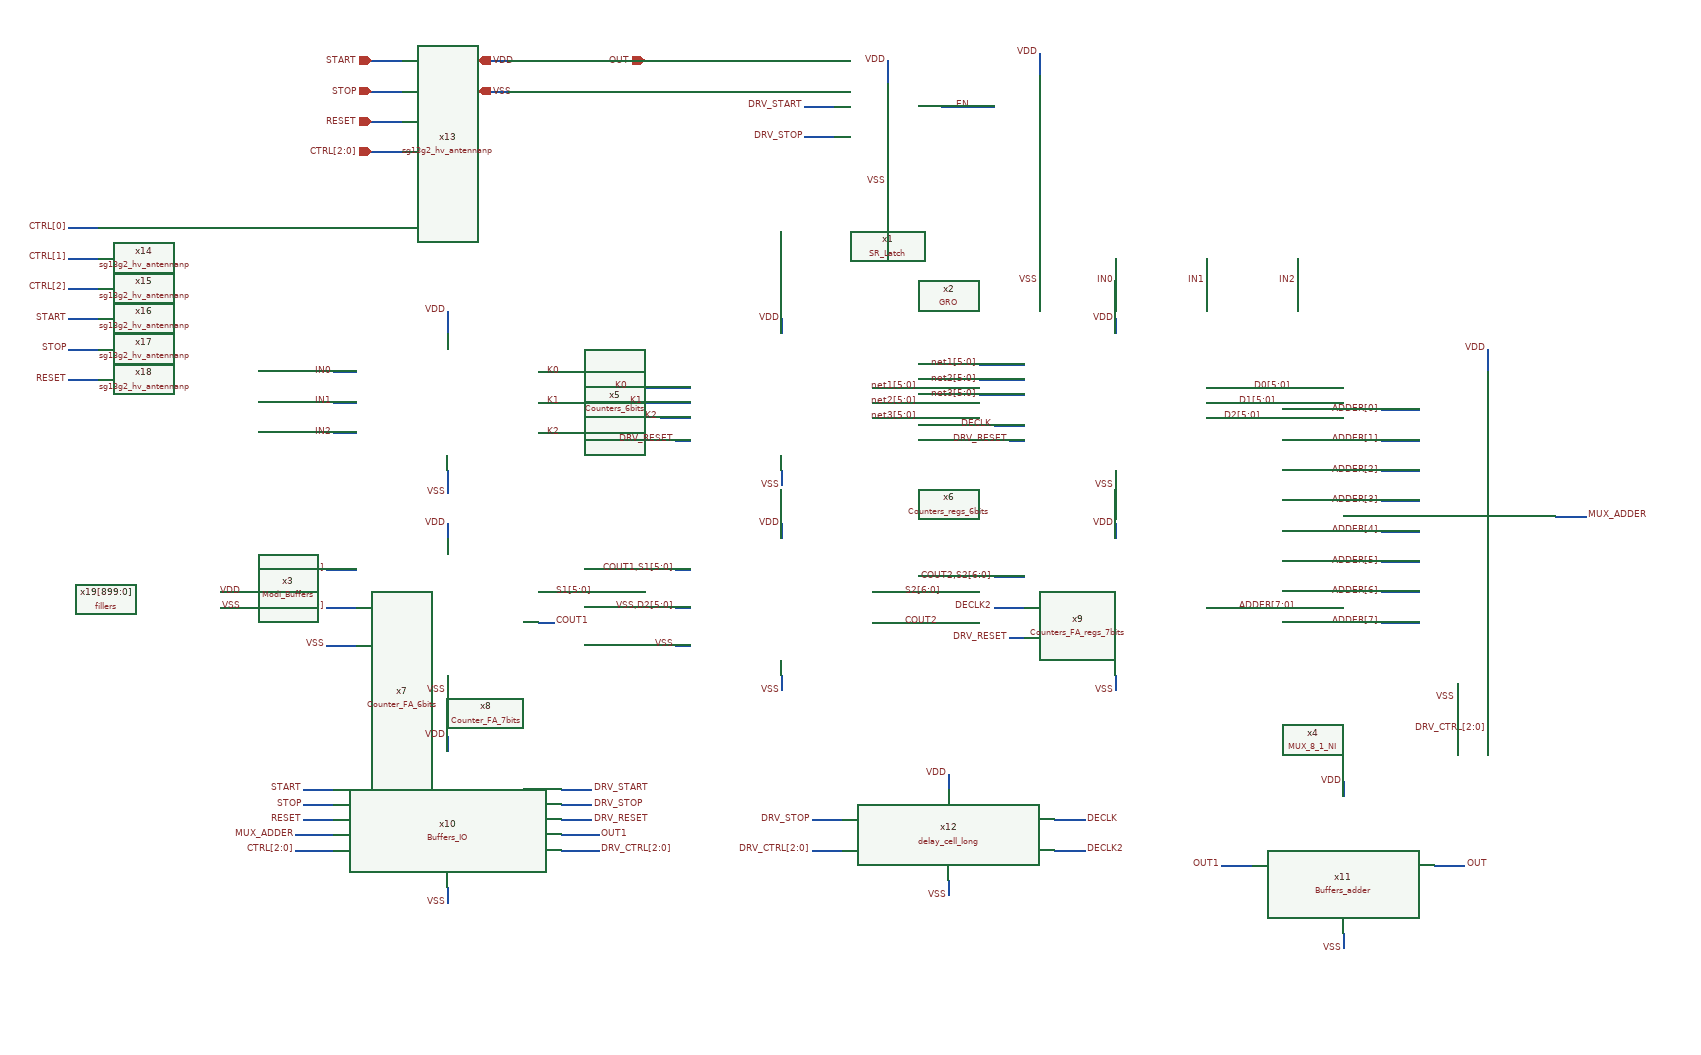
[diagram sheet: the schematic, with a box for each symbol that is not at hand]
v {xschem version=3.4.8RC file_version=1.3}
G {}
K {}
V {}
S {}
F {}
E {}
N 760 -850 760 -830 {lab=VDD}
N 1200 -850 1200 -830 {lab=VDD}
N 760 -650 760 -630 {lab=VSS}
N 1200 -650 1200 -630 {lab=VSS}
N 320 -580 320 -560 {lab=VDD}
N 760 -580 760 -560 {lab=VDD}
N 320 -380 320 -360 {lab=VSS}
N 760 -380 760 -360 {lab=VSS}
N 880 -490 920 -490 {lab=S2[6:0]}
N 880 -450 920 -450 {lab=COUT2}
N 1320 -760 1380 -760 {lab=D0[5:0]}
N 1320 -740 1360 -740 {lab=D1[5:0]}
N 1320 -720 1340 -720 {lab=D2[5:0]}
N 1040 -710 1080 -710 {lab=DECLK}
N 1060 -690 1080 -690 {lab=DRV_RESET}
N 880 -760 940 -760 {lab=net1[5:0]}
N 880 -720 940 -720 {lab=net3[5:0]}
N 620 -690 640 -690 {lab=DRV_RESET}
N 600 -720 640 -720 {lab=K2}
N 580 -740 640 -740 {lab=K1}
N 560 -760 640 -760 {lab=K0}
N 160 -520 200 -520 {lab=D0[5:0]}
N 160 -470 200 -470 {lab=D1[5:0]}
N 160 -420 200 -420 {lab=VSS}
N 440 -490 460 -490 {lab=S1[5:0]}
N 440 -450 460 -450 {lab=COUT1}
N 620 -420 640 -420 {lab=VSS}
N 620 -470 640 -470 {lab=VSS,D2[5:0]}
N 620 -520 640 -520 {lab=COUT1,S1[5:0]}
N 1200 -580 1200 -560 {lab=VDD}
N 1200 -380 1200 -360 {lab=VSS}
N 1320 -470 1360 -470 {lab=ADDER[7:0]}
N 1060 -430 1080 -430 {lab=DRV_RESET}
N 1040 -470 1080 -470 {lab=DECLK2}
N 220 -1190 260 -1190 {lab=START}
N 220 -1150 260 -1150 {lab=STOP}
N 220 -1110 260 -1110 {lab=RESET}
N 360 -1190 400 -1190 {lab=VDD}
N 360 -1150 400 -1150 {lab=VSS}
N 580 -1190 620 -1190 {lab=OUT}
N 1040 -510 1080 -510 {lab=COUT2,S2[6:0]}
N 790 -1130 830 -1130 {lab=DRV_START}
N 790 -1090 830 -1090 {lab=DRV_STOP}
N 900 -1190 900 -1160 {lab=VDD}
N 900 -1060 900 -1030 {lab=VSS}
N 1100 -1200 1100 -1170 {lab=VDD}
N 970 -1130 1040 -1130 {lab=EN}
N 1100 -930 1100 -900 {lab=VSS}
N 1200 -930 1200 -900 {lab=IN0}
N 1320 -930 1320 -900 {lab=IN1}
N 1440 -930 1440 -900 {lab=IN2}
N 320 -650 320 -620 {lab=VSS}
N 440 -780 470 -780 {lab=K0}
N 440 -740 470 -740 {lab=K1}
N 440 -700 470 -700 {lab=K2}
N 170 -780 200 -780 {lab=IN0}
N 170 -740 200 -740 {lab=IN1}
N 170 -700 200 -700 {lab=IN2}
N 320 -860 320 -830 {lab=VDD}
N 1690 -810 1690 -780 {lab=VDD}
N 1780 -590 1820 -590 {lab=MUX_ADDER}
N 1550 -730 1600 -730 {lab=ADDER[0]}
N 1550 -690 1600 -690 {lab=ADDER[1]}
N 1550 -650 1600 -650 {lab=ADDER[2]}
N 1550 -610 1600 -610 {lab=ADDER[3]}
N 1550 -570 1600 -570 {lab=ADDER[4]}
N 1550 -530 1600 -530 {lab=ADDER[5]}
N 1550 -490 1600 -490 {lab=ADDER[6]}
N 1550 -450 1600 -450 {lab=ADDER[7]}
N 1650 -370 1650 -350 {lab=VSS}
N 220 -1070 260 -1070 {lab=CTRL[2:0]}
N 320 -100 320 -80 {lab=VSS}
N 320 -300 320 -280 {lab=VDD}
N 130 -230 170 -230 {lab=START}
N 130 -210 170 -210 {lab=STOP}
N 130 -190 170 -190 {lab=RESET}
N 120 -170 170 -170 {lab=MUX_ADDER}
N 470 -230 510 -230 {lab=DRV_START}
N 470 -210 510 -210 {lab=DRV_STOP}
N 470 -190 510 -190 {lab=DRV_RESET}
N 470 -170 520 -170 {lab=OUT1}
N 1690 -370 1690 -310 {lab=DRV_CTRL[2:0]}
N 470 -150 520 -150 {lab=DRV_CTRL[2:0]}
N 120 -150 170 -150 {lab=CTRL[2:0]}
N 980 -110 980 -90 {lab=VSS}
N 980 -250 980 -230 {lab=VDD}
N 800 -190 840 -190 {lab=DRV_STOP}
N 1120 -190 1160 -190 {lab=DECLK}
N 1120 -150 1160 -150 {lab=DECLK2}
N 800 -150 840 -150 {lab=DRV_CTRL[2:0]}
N 1340 -130 1380 -130 {lab=OUT1}
N 1620 -130 1660 -130 {lab=OUT}
N 1500 -240 1500 -220 {lab=VDD}
N 1500 -40 1500 -20 {lab=VSS}
N -180 -970 -140 -970 {lab=CTRL[0]}
N -180 -930 -140 -930 {lab=CTRL[1]}
N -180 -890 -140 -890 {lab=CTRL[2]}
N -180 -850 -140 -850 {lab=START}
N -180 -810 -140 -810 {lab=STOP}
N -180 -770 -140 -770 {lab=RESET}
N 880 -740 940 -740 {lab=net2[5:0]}
N 1020 -790 1080 -790 {lab=net1[5:0]}
N 1020 -750 1080 -750 {lab=net3[5:0]}
N 1020 -770 1080 -770 {lab=net2[5:0]}
N 20 -470 50 -470 {lab=VSS}
N 20 -490 50 -490 {lab=VDD}
C {Counters_6bits.sym} 540 -590 0 0 {name=x5
}
C {Counters_regs_6bits.sym} 980 -560 0 0 {name=x6
}
C {Counter_FA_6bits.sym} 180 -380 0 0 {name=x7
}
C {Counter_FA_7bits.sym} 380 -300 0 0 {name=x8
}
C {lab_wire.sym} 760 -630 0 0 {name=p9 sig_type=std_logic lab=VSS
}
C {lab_wire.sym} 1200 -630 0 0 {name=p10 sig_type=std_logic lab=VSS
}
C {lab_wire.sym} 760 -360 0 0 {name=p11 sig_type=std_logic lab=VSS
}
C {lab_wire.sym} 320 -360 0 0 {name=p12 sig_type=std_logic lab=VSS
}
C {lab_wire.sym} 760 -850 0 0 {name=p13 sig_type=std_logic lab=VDD
}
C {lab_wire.sym} 1200 -850 0 0 {name=p14 sig_type=std_logic lab=VDD
}
C {lab_wire.sym} 760 -580 0 0 {name=p15 sig_type=std_logic lab=VDD
}
C {lab_wire.sym} 320 -580 0 0 {name=p16 sig_type=std_logic lab=VDD
}
C {lab_wire.sym} 580 -740 3 0 {name=p18 sig_type=std_logic lab=K1
}
C {lab_wire.sym} 560 -760 3 0 {name=p17 sig_type=std_logic lab=K0
}
C {lab_wire.sym} 600 -720 3 0 {name=p19 sig_type=std_logic lab=K2
}
C {lab_wire.sym} 1040 -710 3 0 {name=p21 sig_type=std_logic lab=DECLK
}
C {lab_wire.sym} 1060 -690 3 0 {name=p22 sig_type=std_logic lab=DRV_RESET
}
C {lab_wire.sym} 620 -520 0 0 {name=p23 sig_type=std_logic lab=COUT1,S1[5:0]
}
C {lab_wire.sym} 1380 -760 0 1 {name=p24 sig_type=std_logic lab=D0[5:0]
}
C {lab_wire.sym} 1360 -740 0 1 {name=p25 sig_type=std_logic lab=D1[5:0]
}
C {lab_wire.sym} 1340 -720 0 1 {name=p26 sig_type=std_logic lab=D2[5:0]
}
C {lab_wire.sym} 160 -520 0 0 {name=p27 sig_type=std_logic lab=D0[5:0]
}
C {lab_wire.sym} 160 -470 0 0 {name=p28 sig_type=std_logic lab=D1[5:0]
}
C {lab_wire.sym} 620 -470 0 0 {name=p29 sig_type=std_logic lab=VSS,D2[5:0]
}
C {lab_wire.sym} 160 -420 0 0 {name=p30 sig_type=std_logic lab=VSS
}
C {lab_wire.sym} 620 -420 0 0 {name=p31 sig_type=std_logic lab=VSS
}
C {lab_wire.sym} 460 -490 0 1 {name=p32 sig_type=std_logic lab=S1[5:0]
}
C {lab_wire.sym} 460 -450 0 1 {name=p33 sig_type=std_logic lab=COUT1
}
C {lab_wire.sym} 920 -450 0 1 {name=p35 sig_type=std_logic lab=COUT2
}
C {lab_wire.sym} 1200 -580 0 0 {name=p36 sig_type=std_logic lab=VDD
}
C {lab_wire.sym} 1200 -360 0 0 {name=p37 sig_type=std_logic lab=VSS
}
C {Counters_FA_regs_7bits.sym} 1040 -350 0 0 {name=x9
}
C {lab_wire.sym} 1360 -470 0 1 {name=p39 sig_type=std_logic lab=ADDER[7:0]
}
C {ipin.sym} 220 -1190 0 0 {name=p40 lab=START}
C {ipin.sym} 220 -1150 0 0 {name=p41 lab=STOP}
C {ipin.sym} 220 -1110 0 0 {name=p42 lab=RESET}
C {iopin.sym} 360 -1190 0 1 {name=p46 lab=VDD}
C {iopin.sym} 360 -1150 0 1 {name=p47 lab=VSS}
C {opin.sym} 580 -1190 0 1 {name=p48 lab=OUT}
C {lab_wire.sym} 920 -490 0 1 {name=p49 sig_type=std_logic lab=S2[6:0]
}
C {lab_wire.sym} 1040 -510 0 0 {name=p50 sig_type=std_logic lab=COUT2,S2[6:0]
}
C {lab_wire.sym} 900 -1030 0 0 {name=p2 sig_type=std_logic lab=VSS
}
C {lab_wire.sym} 1100 -1200 0 0 {name=p1 sig_type=std_logic lab=VDD
}
C {SR_Latch.sym} 810 -1020 0 0 {name=x1}
C {lab_wire.sym} 900 -1190 0 0 {name=p3 sig_type=std_logic lab=VDD
}
C {lab_wire.sym} 790 -1130 0 0 {name=p4 sig_type=std_logic lab=DRV_START
}
C {lab_wire.sym} 790 -1090 0 0 {name=p5 sig_type=std_logic lab=DRV_STOP
}
C {lab_wire.sym} 1010 -1130 0 0 {name=p6 sig_type=std_logic lab=EN
}
C {GRO.sym} 1040 -910 0 0 {name=x2
}
C {lab_wire.sym} 1100 -900 0 0 {name=p7 sig_type=std_logic lab=VSS
}
C {lab_wire.sym} 1200 -900 0 0 {name=p8 sig_type=std_logic lab=IN0
}
C {lab_wire.sym} 1320 -900 0 0 {name=p43 sig_type=std_logic lab=IN1
}
C {lab_wire.sym} 1440 -900 0 0 {name=p44 sig_type=std_logic lab=IN2
}
C {lab_wire.sym} 320 -620 0 0 {name=p51 sig_type=std_logic lab=VSS
}
C {Modi_Buffers.sym} 100 -560 0 0 {name=x3
}
C {lab_wire.sym} 470 -780 3 1 {name=p52 sig_type=std_logic lab=K0
}
C {lab_wire.sym} 470 -740 3 1 {name=p53 sig_type=std_logic lab=K1
}
C {lab_wire.sym} 470 -700 3 1 {name=p54 sig_type=std_logic lab=K2
}
C {lab_wire.sym} 170 -780 1 0 {name=p55 sig_type=std_logic lab=IN0
}
C {lab_wire.sym} 170 -740 1 0 {name=p56 sig_type=std_logic lab=IN1
}
C {lab_wire.sym} 170 -700 1 0 {name=p57 sig_type=std_logic lab=IN2
}
C {lab_wire.sym} 320 -860 0 0 {name=p58 sig_type=std_logic lab=VDD
}
C {lab_wire.sym} 1690 -810 0 0 {name=p59 sig_type=std_logic lab=VDD
}
C {lab_wire.sym} 1550 -730 0 0 {name=p60 sig_type=std_logic lab=ADDER[0]
}
C {lab_wire.sym} 1550 -690 0 0 {name=p61 sig_type=std_logic lab=ADDER[1]
}
C {lab_wire.sym} 1550 -650 0 0 {name=p62 sig_type=std_logic lab=ADDER[2]
}
C {lab_wire.sym} 1550 -610 0 0 {name=p63 sig_type=std_logic lab=ADDER[3]
}
C {lab_wire.sym} 1550 -570 0 0 {name=p64 sig_type=std_logic lab=ADDER[4]
}
C {lab_wire.sym} 1550 -530 0 0 {name=p65 sig_type=std_logic lab=ADDER[5]
}
C {lab_wire.sym} 1550 -490 0 0 {name=p66 sig_type=std_logic lab=ADDER[6]
}
C {lab_wire.sym} 1550 -450 0 0 {name=p67 sig_type=std_logic lab=ADDER[7]
}
C {lab_wire.sym} 1820 -590 0 1 {name=p68 sig_type=std_logic lab=MUX_ADDER
}
C {lab_wire.sym} 1650 -350 0 0 {name=p69 sig_type=std_logic lab=VSS
}
C {ipin.sym} 220 -1070 0 0 {name=p70 lab=CTRL[2:0]}
C {lab_wire.sym} 320 -80 0 0 {name=p71 sig_type=std_logic lab=VSS
}
C {lab_wire.sym} 320 -300 0 0 {name=p72 sig_type=std_logic lab=VDD
}
C {lab_wire.sym} 130 -230 0 0 {name=p73 sig_type=std_logic lab=START
}
C {lab_wire.sym} 130 -210 0 0 {name=p74 sig_type=std_logic lab=STOP
}
C {lab_wire.sym} 130 -190 0 0 {name=p75 sig_type=std_logic lab=RESET
}
C {lab_wire.sym} 120 -170 0 0 {name=p76 sig_type=std_logic lab=MUX_ADDER
}
C {lab_wire.sym} 510 -230 0 1 {name=p84 sig_type=std_logic lab=DRV_START
}
C {lab_wire.sym} 510 -210 0 1 {name=p85 sig_type=std_logic lab=DRV_STOP
}
C {lab_wire.sym} 510 -190 0 1 {name=p86 sig_type=std_logic lab=DRV_RESET
}
C {lab_wire.sym} 520 -170 0 1 {name=p87 sig_type=std_logic lab=OUT1
}
C {Buffers_IO.sym} 320 -190 0 0 {name=x10}
C {lab_wire.sym} 1690 -310 0 0 {name=p77 sig_type=std_logic lab=DRV_CTRL[2:0]
}
C {lab_wire.sym} 520 -150 0 1 {name=p78 sig_type=std_logic lab=DRV_CTRL[2:0]
}
C {lab_wire.sym} 120 -150 0 0 {name=p79 sig_type=std_logic lab=CTRL[2:0]
}
C {lab_wire.sym} 980 -90 0 0 {name=p45 sig_type=std_logic lab=VSS
}
C {lab_wire.sym} 980 -250 0 0 {name=p80 sig_type=std_logic lab=VDD
}
C {lab_wire.sym} 800 -190 0 0 {name=p81 sig_type=std_logic lab=DRV_STOP
}
C {lab_wire.sym} 1160 -190 0 1 {name=p82 sig_type=std_logic lab=DECLK
}
C {lab_wire.sym} 1160 -150 0 1 {name=p83 sig_type=std_logic lab=DECLK2
}
C {MUX_8_1_NI.sym} 1480 -520 0 0 {name=x4}
C {delay_cell_long.sym} 1000 -170 0 0 {name=x12}
C {lab_wire.sym} 800 -150 3 0 {name=p88 sig_type=std_logic lab=DRV_CTRL[2:0]
}
C {lab_wire.sym} 1060 -430 3 0 {name=p38 sig_type=std_logic lab=DRV_RESET
}
C {lab_wire.sym} 1040 -470 3 0 {name=p34 sig_type=std_logic lab=DECLK2
}
C {lab_wire.sym} 620 -690 3 0 {name=p20 sig_type=std_logic lab=DRV_RESET
}
C {lab_wire.sym} 1340 -130 0 0 {name=p98 sig_type=std_logic lab=OUT1
}
C {lab_wire.sym} 1660 -130 0 1 {name=p101 sig_type=std_logic lab=OUT
}
C {Buffers_adder.sym} 1280 50 0 0 {name=x11}
C {lab_wire.sym} 1500 -240 0 0 {name=p89 sig_type=std_logic lab=VDD
}
C {lab_wire.sym} 1500 -20 0 0 {name=p90 sig_type=std_logic lab=VSS
}
C {lab_wire.sym} -180 -970 0 0 {name=p91 sig_type=std_logic lab=CTRL[0]
}
C {sg13g2_hv_antennanp.sym} -50 -970 0 0 {name=x13 VDD=VDD VSS=VSS prefix=sg13g2_hv_ }
C {lab_wire.sym} -180 -930 0 0 {name=p92 sig_type=std_logic lab=CTRL[1]
}
C {sg13g2_hv_antennanp.sym} -50 -930 0 0 {name=x14 VDD=VDD VSS=VSS prefix=sg13g2_hv_ }
C {lab_wire.sym} -180 -890 0 0 {name=p93 sig_type=std_logic lab=CTRL[2]
}
C {sg13g2_hv_antennanp.sym} -50 -890 0 0 {name=x15 VDD=VDD VSS=VSS prefix=sg13g2_hv_ }
C {lab_wire.sym} -180 -850 0 0 {name=p94 sig_type=std_logic lab=START
}
C {sg13g2_hv_antennanp.sym} -50 -850 0 0 {name=x16 VDD=VDD VSS=VSS prefix=sg13g2_hv_ }
C {lab_wire.sym} -180 -810 0 0 {name=p95 sig_type=std_logic lab=STOP
}
C {sg13g2_hv_antennanp.sym} -50 -810 0 0 {name=x17 VDD=VDD VSS=VSS prefix=sg13g2_hv_ }
C {lab_wire.sym} -180 -770 0 0 {name=p96 sig_type=std_logic lab=RESET
}
C {sg13g2_hv_antennanp.sym} -50 -770 0 0 {name=x18 VDD=VDD VSS=VSS prefix=sg13g2_hv_ }
C {lab_wire.sym} 940 -760 0 0 {name=p100 sig_type=std_logic lab=net1[5:0]
}
C {lab_wire.sym} 940 -740 0 0 {name=p102 sig_type=std_logic lab=net2[5:0]
}
C {lab_wire.sym} 940 -720 0 0 {name=p103 sig_type=std_logic lab=net3[5:0]
}
C {lab_wire.sym} 1020 -790 0 0 {name=p104 sig_type=std_logic lab=net1[5:0]
}
C {lab_wire.sym} 1020 -770 0 0 {name=p105 sig_type=std_logic lab=net2[5:0]
}
C {lab_wire.sym} 1020 -750 0 0 {name=p106 sig_type=std_logic lab=net3[5:0]
}
C {fillers.sym} -130 -480 0 0 {name=x19[899:0]}
C {lab_wire.sym} 50 -490 0 0 {name=p97 sig_type=std_logic lab=VDD
}
C {lab_wire.sym} 50 -470 0 0 {name=p99 sig_type=std_logic lab=VSS
}
